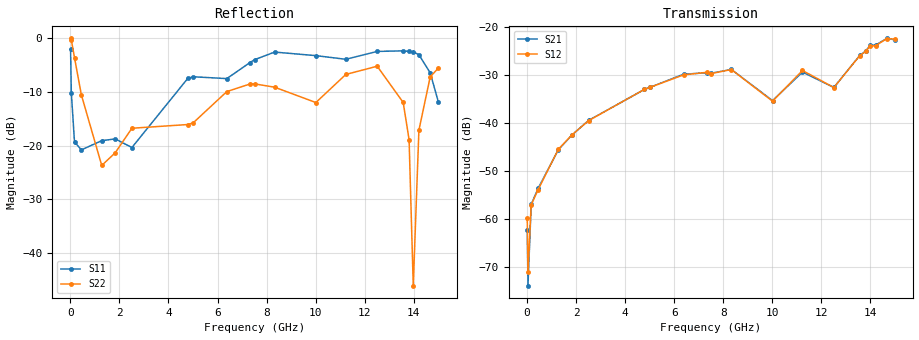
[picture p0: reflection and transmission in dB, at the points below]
!Agilent Technologies,N5230A,MY45001650,A.07.50.48
!Agilent N5230A: A.07.50.48
!Date: Wednesday, April 30, 2014 16:49:29
!Correction: S11(Full 2 Port(1,2))
!S21(Full 2 Port(1,2))
!S12(Full 2 Port(1,2))
!S22(Full 2 Port(1,2))
!S2P File: Measurements: S11, S21, S12, S22:
# Hz S  dB  R 50
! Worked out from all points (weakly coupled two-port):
!   1500 points, 10 MHz to 15 GHz, reference 50 ohm
!   highest |S21| = -22.41 dB at 14.67 GHz (marker M1); lowest = -73.9 dB at 40 MHz (marker M2)
!   lowest |S11| = -20.8 dB at 450 MHz (marker M3), VSWR 1.20, Z = 56.7 - j7.09 ohm
!   |S11| at or under -10 dB: 39.14 MHz to 4.103 GHz (4.064 GHz wide, 196 % of centre); 14.88 GHz to end of sweep
!   |S22| runs from -46.0 to -0.1 dB; largest |S21 - S12| = 0.0029
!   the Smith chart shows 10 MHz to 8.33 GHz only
!   S11 on the Smith chart (normalised r, x): 10 MHz: 1.16, -2.72; 1.83 GHz: 0.88, -0.18; 4.79 GHz: 1.54, -1.02; 6.38 GHz: 0.42, -0.14; 7.32 GHz: 0.44, +0.80; 8.33 GHz: 2.37, +3.09
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1e7  -2.11 -35.1  -62.31 -146.6  -59.78 59.4  -0.07 -4.6
4e7  -10.17 -60.9  -73.92 45.7  -71.15 35.3  -0.35 -17.7
1.7e8  -19.33 -46.7  -57.01 -10.9  -57.08 -35.8  -3.67 -60.5
4.5e8  -20.80 -42.8  -53.67 -94.5  -53.97 -96.3  -10.58 -106.8
1.28e9  -19.09 -83.3  -45.59 169.3  -45.49 169.7  -23.70 144.3
1.83e9  -18.76 -119.0  -42.55 125.4  -42.52 124.4  -21.34 55.5
2.51e9  -20.36 176.4  -39.50 71.4  -39.55 71.0  -16.78 9.0
4.79e9  -7.50 -40.3  -33.04 -94.9  -33.02 -95.0  -16.09 -115.2
5.01e9  -7.21 -52.9  -32.62 -109.9  -32.62 -110.0  -15.77 -134.9
6.38e9  -7.55 -160.6  -29.88 153.5  -30.02 153.9  -9.96 140.0
7.32e9  -4.58 96.0  -29.58 83.5  -29.49 83.3  -8.56 105.2
7.51e9  -4.03 80.2  -29.66 70.3  -29.74 70.5  -8.53 98.9
8.33e9  -2.62 23.6  -28.89 8.9  -28.90 8.9  -9.15 62.9
1.001e10  -3.28 -67.0  -35.37 -110.9  -35.50 -111.2  -12.00 -42.2
1.123e10  -3.96 178.5  -29.44 -169.9  -29.10 -168.4  -6.78 -121.7
1.251e10  -2.50 71.7  -32.63 111.8  -32.65 112.7  -5.25 -155.0
1.357e10  -2.39 31.8  -25.94 2.4  -25.98 2.7  -11.99 -179.7
1.381e10  -2.50 21.5  -25.02 -26.4  -25.13 -26.3  -18.90 169.4
1.398e10  -2.55 14.0  -23.88 -49.1  -23.99 -47.8  -46.05 127.4
1.421e10  -3.12 1.4  -23.83 -80.9  -23.94 -80.9  -17.15 -15.4
1.467e10  -6.47 -42.9  -22.41 -127.3  -22.45 -126.9  -7.23 -28.9
1.5e10  -11.83 -126.6  -22.72 -162.5  -22.57 -162.4  -5.61 -35.9
